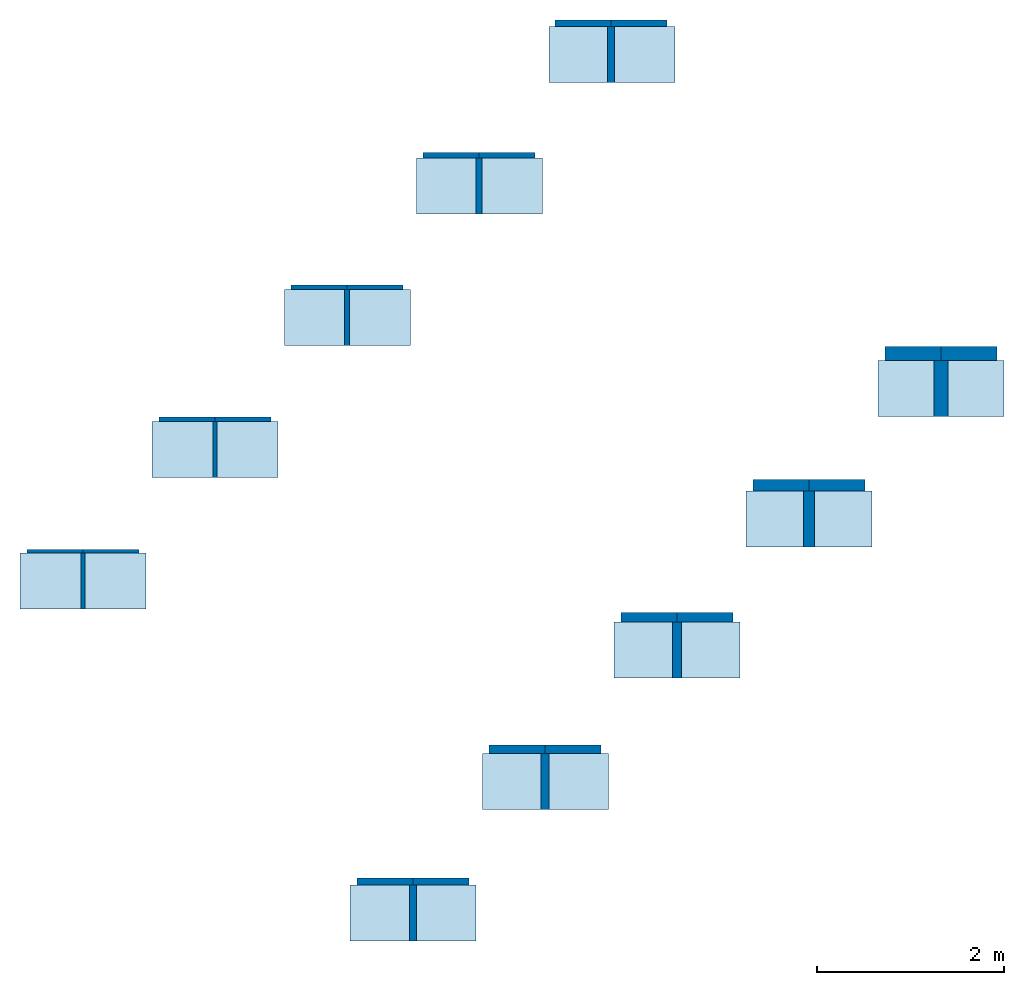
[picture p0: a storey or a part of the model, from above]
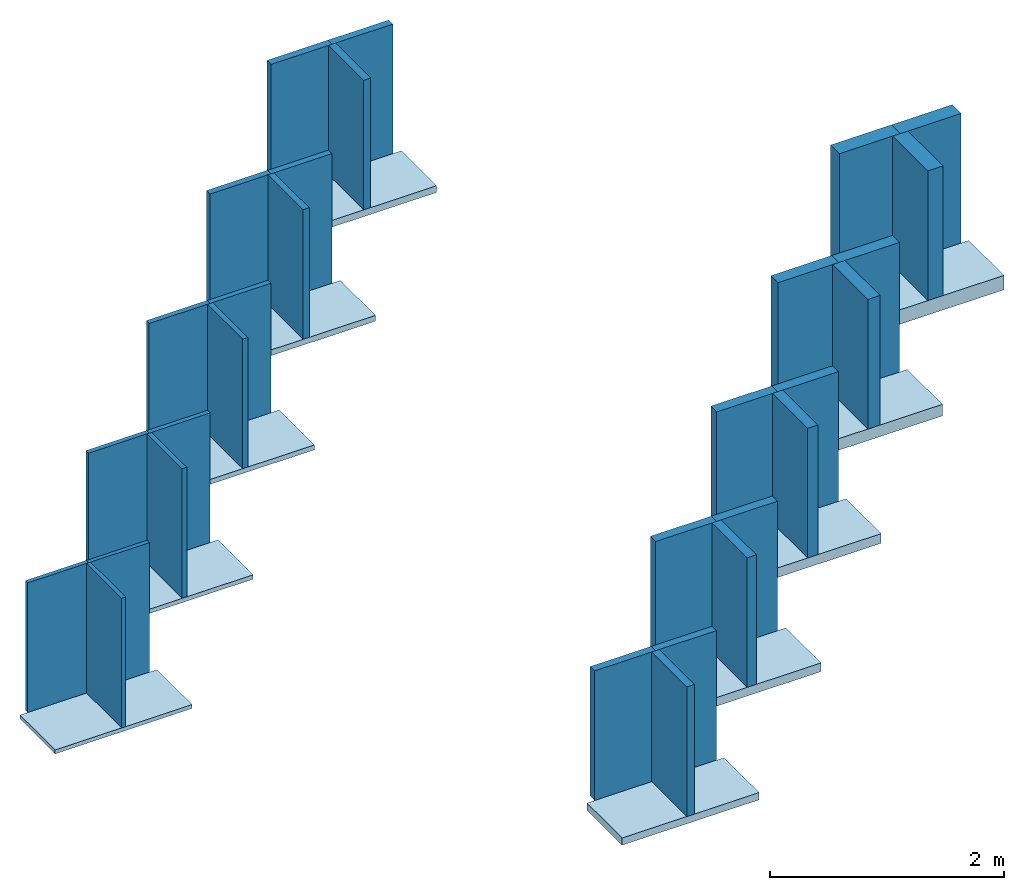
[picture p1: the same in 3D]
Properties of the parts of a building model (IFC2X3)

# File
Description: ViewDefinition [CoordinationView_V2.0, QuantityTakeOffAddOnView]
Time: 2023-01-18T09:23:17
Written by: The EXPRESS Data Manager Version 5.02.0100.07 : 28 Aug 2013
Made in: 21.1.70.21 - Exporter 21.1.70.21 - Alternate UI 21.1.70.21
Comment: STEP Physical File produced by: The EXPRESS Data Manager Version 5.02.0100.07 : 28 Aug 2013 * Module: EDMstepFileFactory/EDMstandAlone * Creation date: Wed Jan 18 09:23:17 2023 * Host: BIM-LT03 * Database: C:\Users\DONNEE~1\AppData\Local\Temp\6dfd9f73-01cb-4fe2-bb7c-203e315a706e\c4da6f99-adb1-409d-b0d4-b091b76bd9ac\ifc * Database version: 5507 * Database creation date: Wed Jan 18 09:23:16 2023 * Schema: IFC2X3 * Model: DataRepository.ifc * Model creation date: Wed Jan 18 09:23:16 2023 * Header model: DataRepository.ifc_HeaderModel * Header model creation date: Wed Jan 18 09:23:16 2023 * EDMuser: sdai-user * EDMgroup: sdai-group * License ID and type: 5605 : Permanent license. Expiry date: * EDMstepFileFactory options: 020000

# IfcSite, Default
RefLatitude: 42, 24, 53, 508911; RefLongitude: -71, -15, -29, -58837; RefElevation: 0 mm
Pset_ProductRequirements - Category: Project Information

# IfcBuilding
Pset_BuildingCommon - NumberOfStoreys: 1
Pset_ProductRequirements - Category: Project Information

# IfcBuildingStorey: Level:NL_00_niveau, Begane grond
LongName: Begane grond; Elevation: 0 mm
Pset_AirSideSystemInformation - Name: Begane grond
Pset_ProductRequirements - Name: Begane grond; Category: Levels

# IfcSlab: Floor:NLRS_23_FL_Acoustifit_100x600x1350mm, Floor:NLRS_23_FL_Acoustifit_100x600x1350mm:6533
In: Begane grond
Type - PredefinedType: FLOOR; Material: Knauf Insulation_Ecose® glaswol Acoustifit 100 mm
Type - Pset_ElementShading - Roughness: 304.8 mm
Type - Pset_ManufacturerTypeInformation - Manufacturer: Knauf Insulation B.V.
Type - Pset_ProductRequirements - Category: Floors
Type - Pset_QuantityTakeOff - Reference: Floor:NLRS_23_FL_Acoustifit_100x600x1350mm
Type - Pset_ReinforcementBarPitchOfSlab - Description: Acoustifit - 100mm; Reference: Floor:NLRS_23_FL_Acoustifit_100x600x1350mm
Type - Pset_SlabCommon - IsExternal: no; Reference: Floor:NLRS_23_FL_Acoustifit_100x600x1350mm; ThermalTransmittance: 0.37 kg/K/s3
Type - Pset_Floor_Acoustifit_LOD_200 - Assembly Code: 23; Type Image: Raster image: Acoustifit.jpg (2); Model: Acoustifit is een onbeklede glaswolplaat met ECOSE® Technology.; Manufacturer: Knauf Insulation B.V.; URL: www.knaufinsulation.nl; Description: Acoustifit - 100mm
Classification: 23 Vloeren (NL-SfB)
Pset_SlabCommon - LoadBearing: no; PitchAngle: 0 deg
Pset_Floor_Acoustifit_LOD_200 - Type: Floor: NLRS_23_FL_Acoustifit_100x600x1350mm
BaseQuantities - GrossArea: 0.81 m2; NetArea: 2.01 m2; GrossVolume: 81 m3; NetVolume: 0.081 m3; Perimeter: 3900 mm; Width: 100 mm

# IfcSlab: Floor:NLRS_23_FL_Acoustifit_120x600x1350mm, Floor:NLRS_23_FL_Acoustifit_120x600x1350mm:6542
In: Begane grond
Type - PredefinedType: FLOOR; Material: Knauf Insulation_Ecose® glaswol Acoustifit 120 mm
Type - Pset_ElementShading - Roughness: 304.8 mm
Type - Pset_ManufacturerTypeInformation - Manufacturer: Knauf Insulation B.V.
Type - Pset_ProductRequirements - Category: Floors
Type - Pset_QuantityTakeOff - Reference: Floor:NLRS_23_FL_Acoustifit_120x600x1350mm
Type - Pset_ReinforcementBarPitchOfSlab - Description: Acoustifit - 120mm; Reference: Floor:NLRS_23_FL_Acoustifit_120x600x1350mm
Type - Pset_SlabCommon - IsExternal: no; Reference: Floor:NLRS_23_FL_Acoustifit_120x600x1350mm; ThermalTransmittance: 0.308333 kg/K/s3
Type - Pset_Floor_Acoustifit_LOD_200 - Assembly Code: 23; Type Image: Raster image: Acoustifit.jpg (2); Model: Acoustifit is een onbeklede glaswolplaat met ECOSE® Technology.; Manufacturer: Knauf Insulation B.V.; URL: www.knaufinsulation.nl; Description: Acoustifit - 120mm
Classification: 23 Vloeren (NL-SfB)
Pset_SlabCommon - LoadBearing: no; PitchAngle: 0 deg
Pset_Floor_Acoustifit_LOD_200 - Type: Floor: NLRS_23_FL_Acoustifit_120x600x1350mm
BaseQuantities - GrossArea: 0.81 m2; NetArea: 2.088 m2; GrossVolume: 97.2 m3; NetVolume: 0.0972 m3; Perimeter: 3900 mm; Width: 120 mm

# IfcSlab: Floor:NLRS_23_FL_Acoustifit_150x600x1350mm, Floor:NLRS_23_FL_Acoustifit_150x600x1350mm:6551
In: Begane grond
Type - PredefinedType: FLOOR; Material: Knauf Insulation_Ecose® glaswol Acoustifit 150 mm
Type - Pset_ElementShading - Roughness: 304.8 mm
Type - Pset_ManufacturerTypeInformation - Manufacturer: Knauf Insulation B.V.
Type - Pset_ProductRequirements - Category: Floors
Type - Pset_QuantityTakeOff - Reference: Floor:NLRS_23_FL_Acoustifit_150x600x1350mm
Type - Pset_ReinforcementBarPitchOfSlab - Description: Acoustifit - 150mm; Reference: Floor:NLRS_23_FL_Acoustifit_150x600x1350mm
Type - Pset_SlabCommon - IsExternal: no; Reference: Floor:NLRS_23_FL_Acoustifit_150x600x1350mm; ThermalTransmittance: 0.246667 kg/K/s3
Type - Pset_Floor_Acoustifit_LOD_200 - Assembly Code: 23; Type Image: Raster image: Acoustifit.jpg (2); Model: Acoustifit is een onbeklede glaswolplaat met ECOSE® Technology.; Manufacturer: Knauf Insulation B.V.; URL: www.knaufinsulation.nl; Description: Acoustifit - 150mm
Classification: 23 Vloeren (NL-SfB)
Pset_SlabCommon - LoadBearing: no; PitchAngle: 0 deg
Pset_Floor_Acoustifit_LOD_200 - Type: Floor: NLRS_23_FL_Acoustifit_150x600x1350mm
BaseQuantities - GrossArea: 0.81 m2; NetArea: 2.205 m2; GrossVolume: 121.5 m3; NetVolume: 0.1215 m3; Perimeter: 3900 mm; Width: 150 mm

# IfcSlab: Floor:NLRS_23_FL_Acoustifit_40x600x1350mm, Floor:NLRS_23_FL_Acoustifit_40x600x1350mm:3702
In: Begane grond
Type - PredefinedType: FLOOR; Material: Knauf Insulation_Ecose® glaswol Acoustifit 40 mm
Type - Pset_ElementShading - Roughness: 304.8 mm
Type - Pset_ManufacturerTypeInformation - Manufacturer: Knauf Insulation B.V.
Type - Pset_ProductRequirements - Category: Floors
Type - Pset_QuantityTakeOff - Reference: Floor:NLRS_23_FL_Acoustifit_40x600x1350mm
Type - Pset_ReinforcementBarPitchOfSlab - Description: Acoustifit - 40mm; Reference: Floor:NLRS_23_FL_Acoustifit_40x600x1350mm
Type - Pset_SlabCommon - IsExternal: no; Reference: Floor:NLRS_23_FL_Acoustifit_40x600x1350mm; ThermalTransmittance: 0.925 kg/K/s3
Type - Pset_Floor_Acoustifit_LOD_200 - Assembly Code: 23; Type Image: Raster image: Acoustifit.jpg (2); Model: Acoustifit is een onbeklede glaswolplaat met ECOSE® Technology.; Manufacturer: Knauf Insulation B.V.; URL: www.knaufinsulation.nl; Description: Acoustifit - 40mm
Classification: 23 Vloeren (NL-SfB)
Pset_SlabCommon - LoadBearing: no; PitchAngle: 0 deg
Pset_Floor_Acoustifit_LOD_200 - Type: Floor: NLRS_23_FL_Acoustifit_40x600x1350mm
BaseQuantities - GrossArea: 0.81 m2; NetArea: 1.776 m2; GrossVolume: 32.4 m3; NetVolume: 0.0324 m3; Perimeter: 3900 mm; Width: 40 mm

# IfcSlab: Floor:NLRS_23_FL_Acoustifit_45x600x1350mm, Floor:NLRS_23_FL_Acoustifit_45x600x1350mm:5869
In: Begane grond
Type - PredefinedType: FLOOR; Material: Knauf Insulation_Ecose® glaswol Acoustifit 45 mm
Type - Pset_ElementShading - Roughness: 304.8 mm
Type - Pset_ManufacturerTypeInformation - Manufacturer: Knauf Insulation B.V.
Type - Pset_ProductRequirements - Category: Floors
Type - Pset_QuantityTakeOff - Reference: Floor:NLRS_23_FL_Acoustifit_45x600x1350mm
Type - Pset_ReinforcementBarPitchOfSlab - Description: Acoustifit - 45mm; Reference: Floor:NLRS_23_FL_Acoustifit_45x600x1350mm
Type - Pset_SlabCommon - IsExternal: no; Reference: Floor:NLRS_23_FL_Acoustifit_45x600x1350mm; ThermalTransmittance: 0.822222 kg/K/s3
Type - Pset_Floor_Acoustifit_LOD_200 - Assembly Code: 23; Type Image: Raster image: Acoustifit.jpg (2); Model: Acoustifit is een onbeklede glaswolplaat met ECOSE® Technology.; Manufacturer: Knauf Insulation B.V.; URL: www.knaufinsulation.nl; Description: Acoustifit - 45mm
Classification: 23 Vloeren (NL-SfB)
Pset_SlabCommon - LoadBearing: no; PitchAngle: 0 deg
Pset_Floor_Acoustifit_LOD_200 - Type: Floor: NLRS_23_FL_Acoustifit_45x600x1350mm
BaseQuantities - GrossArea: 0.81 m2; NetArea: 1.7955 m2; GrossVolume: 36.45 m3; NetVolume: 0.03645 m3; Perimeter: 3900 mm; Width: 45 mm

# IfcSlab: Floor:NLRS_23_FL_Acoustifit_50x600x1350mm, Floor:NLRS_23_FL_Acoustifit_50x600x1350mm:5943
In: Begane grond
Type - PredefinedType: FLOOR; Material: Knauf Insulation_Ecose® glaswol Acoustifit 50 mm
Type - Pset_ElementShading - Roughness: 304.8 mm
Type - Pset_ManufacturerTypeInformation - Manufacturer: Knauf Insulation B.V.
Type - Pset_ProductRequirements - Category: Floors
Type - Pset_QuantityTakeOff - Reference: Floor:NLRS_23_FL_Acoustifit_50x600x1350mm
Type - Pset_ReinforcementBarPitchOfSlab - Description: Acoustifit - 50mm; Reference: Floor:NLRS_23_FL_Acoustifit_50x600x1350mm
Type - Pset_SlabCommon - IsExternal: no; Reference: Floor:NLRS_23_FL_Acoustifit_50x600x1350mm; ThermalTransmittance: 0.74 kg/K/s3
Type - Pset_Floor_Acoustifit_LOD_200 - Assembly Code: 23; Type Image: Raster image: Acoustifit.jpg (2); Model: Acoustifit is een onbeklede glaswolplaat met ECOSE® Technology.; Manufacturer: Knauf Insulation B.V.; URL: www.knaufinsulation.nl; Description: Acoustifit - 50mm
Classification: 23 Vloeren (NL-SfB)
Pset_SlabCommon - LoadBearing: no; PitchAngle: 0 deg
Pset_Floor_Acoustifit_LOD_200 - Type: Floor: NLRS_23_FL_Acoustifit_50x600x1350mm
BaseQuantities - GrossArea: 0.81 m2; NetArea: 1.815 m2; GrossVolume: 40.5 m3; NetVolume: 0.0405 m3; Perimeter: 3900 mm; Width: 50 mm

# IfcSlab: Floor:NLRS_23_FL_Acoustifit_60x600x1350mm, Floor:NLRS_23_FL_Acoustifit_60x600x1350mm:5952
In: Begane grond
Type - PredefinedType: FLOOR; Material: Knauf Insulation_Ecose® glaswol Acoustifit 60 mm
Type - Pset_ElementShading - Roughness: 304.8 mm
Type - Pset_ManufacturerTypeInformation - Manufacturer: Knauf Insulation B.V.
Type - Pset_ProductRequirements - Category: Floors
Type - Pset_QuantityTakeOff - Reference: Floor:NLRS_23_FL_Acoustifit_60x600x1350mm
Type - Pset_ReinforcementBarPitchOfSlab - Description: Acoustifit - 60mm; Reference: Floor:NLRS_23_FL_Acoustifit_60x600x1350mm
Type - Pset_SlabCommon - IsExternal: no; Reference: Floor:NLRS_23_FL_Acoustifit_60x600x1350mm; ThermalTransmittance: 0.616667 kg/K/s3
Type - Pset_Floor_Acoustifit_LOD_200 - Assembly Code: 23; Type Image: Raster image: Acoustifit.jpg (2); Model: Acoustifit is een onbeklede glaswolplaat met ECOSE® Technology.; Manufacturer: Knauf Insulation B.V.; URL: www.knaufinsulation.nl; Description: Acoustifit - 60mm
Classification: 23 Vloeren (NL-SfB)
Pset_SlabCommon - LoadBearing: no; PitchAngle: 0 deg
Pset_Floor_Acoustifit_LOD_200 - Type: Floor: NLRS_23_FL_Acoustifit_60x600x1350mm
BaseQuantities - GrossArea: 0.81 m2; NetArea: 1.854 m2; GrossVolume: 48.6 m3; NetVolume: 0.0486 m3; Perimeter: 3900 mm; Width: 60 mm

# IfcSlab: Floor:NLRS_23_FL_Acoustifit_70x600x1350mm, Floor:NLRS_23_FL_Acoustifit_70x600x1350mm:5961
In: Begane grond
Type - PredefinedType: FLOOR; Material: Knauf Insulation_Ecose® glaswol Acoustifit 70 mm
Type - Pset_ElementShading - Roughness: 304.8 mm
Type - Pset_ManufacturerTypeInformation - Manufacturer: Knauf Insulation B.V.
Type - Pset_ProductRequirements - Category: Floors
Type - Pset_QuantityTakeOff - Reference: Floor:NLRS_23_FL_Acoustifit_70x600x1350mm
Type - Pset_ReinforcementBarPitchOfSlab - Description: Acoustifit - 70mm; Reference: Floor:NLRS_23_FL_Acoustifit_70x600x1350mm
Type - Pset_SlabCommon - IsExternal: no; Reference: Floor:NLRS_23_FL_Acoustifit_70x600x1350mm; ThermalTransmittance: 0.528571 kg/K/s3
Type - Pset_Floor_Acoustifit_LOD_200 - Assembly Code: 23; Type Image: Raster image: Acoustifit.jpg (2); Model: Acoustifit is een onbeklede glaswolplaat met ECOSE® Technology.; Manufacturer: Knauf Insulation B.V.; URL: www.knaufinsulation.nl; Description: Acoustifit - 70mm
Classification: 23 Vloeren (NL-SfB)
Pset_SlabCommon - LoadBearing: no; PitchAngle: 0 deg
Pset_Floor_Acoustifit_LOD_200 - Type: Floor: NLRS_23_FL_Acoustifit_70x600x1350mm
BaseQuantities - GrossArea: 0.81 m2; NetArea: 1.893 m2; GrossVolume: 56.7 m3; NetVolume: 0.0567 m3; Perimeter: 3900 mm; Width: 70 mm

# IfcSlab: Floor:NLRS_23_FL_Acoustifit_75x600x1350mm, Floor:NLRS_23_FL_Acoustifit_75x600x1350mm:6406
In: Begane grond
Type - PredefinedType: FLOOR; Material: Knauf Insulation_Ecose® glaswol Acoustifit 75 mm
Type - Pset_ElementShading - Roughness: 304.8 mm
Type - Pset_ManufacturerTypeInformation - Manufacturer: Knauf Insulation B.V.
Type - Pset_ProductRequirements - Category: Floors
Type - Pset_QuantityTakeOff - Reference: Floor:NLRS_23_FL_Acoustifit_75x600x1350mm
Type - Pset_ReinforcementBarPitchOfSlab - Description: Acoustifit - 75mm; Reference: Floor:NLRS_23_FL_Acoustifit_75x600x1350mm
Type - Pset_SlabCommon - IsExternal: no; Reference: Floor:NLRS_23_FL_Acoustifit_75x600x1350mm; ThermalTransmittance: 0.493333 kg/K/s3
Type - Pset_Floor_Acoustifit_LOD_200 - Assembly Code: 23; Type Image: Raster image: Acoustifit.jpg (2); Model: Acoustifit is een onbeklede glaswolplaat met ECOSE® Technology.; Manufacturer: Knauf Insulation B.V.; URL: www.knaufinsulation.nl; Description: Acoustifit - 75mm
Classification: 23 Vloeren (NL-SfB)
Pset_SlabCommon - LoadBearing: no; PitchAngle: 0 deg
Pset_Floor_Acoustifit_LOD_200 - Type: Floor: NLRS_23_FL_Acoustifit_75x600x1350mm
BaseQuantities - GrossArea: 0.81 m2; NetArea: 1.9125 m2; GrossVolume: 60.75 m3; NetVolume: 0.06075 m3; Perimeter: 3900 mm; Width: 75 mm

# IfcSlab: Floor:NLRS_23_FL_Acoustifit_90x600x1350mm, Floor:NLRS_23_FL_Acoustifit_90x600x1350mm:6471
In: Begane grond
Type - PredefinedType: FLOOR; Material: Knauf Insulation_Ecose® glaswol Acoustifit 90 mm
Type - Pset_ElementShading - Roughness: 304.8 mm
Type - Pset_ManufacturerTypeInformation - Manufacturer: Knauf Insulation B.V.
Type - Pset_ProductRequirements - Category: Floors
Type - Pset_QuantityTakeOff - Reference: Floor:NLRS_23_FL_Acoustifit_90x600x1350mm
Type - Pset_ReinforcementBarPitchOfSlab - Description: Acoustifit - 90mm; Reference: Floor:NLRS_23_FL_Acoustifit_90x600x1350mm
Type - Pset_SlabCommon - IsExternal: no; Reference: Floor:NLRS_23_FL_Acoustifit_90x600x1350mm; ThermalTransmittance: 0.411111 kg/K/s3
Type - Pset_Floor_Acoustifit_LOD_200 - Assembly Code: 23; Type Image: Raster image: Acoustifit.jpg (2); Model: Acoustifit is een onbeklede glaswolplaat met ECOSE® Technology.; Manufacturer: Knauf Insulation B.V.; URL: www.knaufinsulation.nl; Description: Acoustifit - 90mm
Classification: 23 Vloeren (NL-SfB)
Pset_SlabCommon - LoadBearing: no; PitchAngle: 0 deg
Pset_Floor_Acoustifit_LOD_200 - Type: Floor: NLRS_23_FL_Acoustifit_90x600x1350mm
BaseQuantities - GrossArea: 0.81 m2; NetArea: 1.971 m2; GrossVolume: 72.9 m3; NetVolume: 0.0729 m3; Perimeter: 3900 mm; Width: 90 mm

# IfcWallStandardCase: Basic Wall:NLRS_21_WA__Acoustifit_100x600x1350mm (3)
In: Begane grond
Type - PredefinedType: STANDARD; Material: Knauf Insulation_Ecose® glaswol Acoustifit 100 mm
Type - Pset_ElementShading - Roughness: 304.8 mm
Type - Pset_ManufacturerTypeInformation - Manufacturer: Knauf Insulation B.V.
Type - Pset_ProductRequirements - Category: Walls
Type - Pset_QuantityTakeOff - Reference: Basic Wall:NLRS_21_WA__Acoustifit_100x600x1350mm
Type - Pset_ReinforcementBarPitchOfWall - Description: Acoustifit - 100mm Acoustifit - 100mm; Reference: Basic Wall:NLRS_21_WA__Acoustifit_100x600x1350mm
Type - Pset_WallCommon - IsExternal: no; Reference: Basic Wall:NLRS_21_WA__Acoustifit_100x600x1350mm; ThermalTransmittance: 0.37 kg/K/s3
Type - Pset_Wall_Acoustifit_LOD_200 - Assembly Code: 21; Type Image: Raster image: Acoustifit.jpg (2); Model: Acoustifit is een onbeklede glaswolplaat met ECOSE® Technology.; Manufacturer: Knauf Insulation B.V.; URL: www.knaufinsulation.nl; Description: Acoustifit - 100mm Acoustifit - 100mm
Classification: 21 Buitenwanden (NL-SfB)
BaseQuantities - Height: 1350 mm; Length: 600 mm; Width: 100 mm; GrossFootprintArea: 0.06 m2; NetVolume: 81000000 m3; NetSideArea: 810000 m2
Pset_WallCommon - IsExternal: yes; ExtendToStructure: no; LoadBearing: no
Pset_Wall_Acoustifit_LOD_200 - Type: Basic Wall: NLRS_21_WA__Acoustifit_100x600x1350mm
Name (Basic Wall:NLRS_21_WA__Acoustifit_100x600x1350mm:...)
4728
4729
4730

# IfcWallStandardCase: Basic Wall:NLRS_21_WA__Acoustifit_120x600x1350mm (3)
In: Begane grond
Type - PredefinedType: STANDARD; Material: Knauf Insulation_Ecose® glaswol Acoustifit 120 mm
Type - Pset_ElementShading - Roughness: 304.8 mm
Type - Pset_ManufacturerTypeInformation - Manufacturer: Knauf Insulation B.V.
Type - Pset_ProductRequirements - Category: Walls
Type - Pset_QuantityTakeOff - Reference: Basic Wall:NLRS_21_WA__Acoustifit_120x600x1350mm
Type - Pset_ReinforcementBarPitchOfWall - Description: Acoustifit - 120mm; Reference: Basic Wall:NLRS_21_WA__Acoustifit_120x600x1350mm
Type - Pset_WallCommon - IsExternal: no; Reference: Basic Wall:NLRS_21_WA__Acoustifit_120x600x1350mm; ThermalTransmittance: 0.308333 kg/K/s3
Type - Pset_Wall_Acoustifit_LOD_200 - Assembly Code: 21; Type Image: Raster image: Acoustifit.jpg (2); Model: Acoustifit is een onbeklede glaswolplaat met ECOSE® Technology.; Manufacturer: Knauf Insulation B.V.; URL: www.knaufinsulation.nl; Description: Acoustifit - 120mm
Classification: 21 Buitenwanden (NL-SfB)
BaseQuantities - Height: 1350 mm; Length: 600 mm; Width: 120 mm; GrossFootprintArea: 0.072 m2; NetVolume: 97200000 m3; NetSideArea: 810000 m2
Pset_WallCommon - IsExternal: yes; ExtendToStructure: no; LoadBearing: no
Pset_Wall_Acoustifit_LOD_200 - Type: Basic Wall: NLRS_21_WA__Acoustifit_120x600x1350mm
Name (Basic Wall:NLRS_21_WA__Acoustifit_120x600x1350mm:...)
4731
4732
4733

# IfcWallStandardCase: Basic Wall:NLRS_21_WA__Acoustifit_150x600x1350mm (3)
In: Begane grond
Type - PredefinedType: STANDARD; Material: Knauf Insulation_Ecose® glaswol Acoustifit 150 mm
Type - Pset_ElementShading - Roughness: 304.8 mm
Type - Pset_ManufacturerTypeInformation - Manufacturer: Knauf Insulation B.V.
Type - Pset_ProductRequirements - Category: Walls
Type - Pset_QuantityTakeOff - Reference: Basic Wall:NLRS_21_WA__Acoustifit_150x600x1350mm
Type - Pset_ReinforcementBarPitchOfWall - Description: Acoustifit - 150mm; Reference: Basic Wall:NLRS_21_WA__Acoustifit_150x600x1350mm
Type - Pset_WallCommon - IsExternal: no; Reference: Basic Wall:NLRS_21_WA__Acoustifit_150x600x1350mm; ThermalTransmittance: 0.246667 kg/K/s3
Type - Pset_Wall_Acoustifit_LOD_200 - Assembly Code: 21; Type Image: Raster image: Acoustifit.jpg (2); Model: Acoustifit is een onbeklede glaswolplaat met ECOSE® Technology.; Manufacturer: Knauf Insulation B.V.; URL: www.knaufinsulation.nl; Description: Acoustifit - 150mm
Classification: 21 Buitenwanden (NL-SfB)
BaseQuantities - Height: 1350 mm; Length: 600 mm; Width: 150 mm; GrossFootprintArea: 0.09 m2; NetVolume: 121500000 m3; NetSideArea: 810000 m2
Pset_WallCommon - IsExternal: yes; ExtendToStructure: no; LoadBearing: no
Pset_Wall_Acoustifit_LOD_200 - Type: Basic Wall: NLRS_21_WA__Acoustifit_150x600x1350mm
Name (Basic Wall:NLRS_21_WA__Acoustifit_150x600x1350mm:...)
4734
4735
4736

# IfcWallStandardCase: Basic Wall:NLRS_21_WA__Acoustifit_40x600x1350mm (3)
In: Begane grond
Type - PredefinedType: STANDARD; Material: Knauf Insulation_Ecose® glaswol Acoustifit 40 mm
Type - Pset_ElementShading - Roughness: 304.8 mm
Type - Pset_ManufacturerTypeInformation - Manufacturer: Knauf Insulation B.V.
Type - Pset_ProductRequirements - Category: Walls
Type - Pset_QuantityTakeOff - Reference: Basic Wall:NLRS_21_WA__Acoustifit_40x600x1350mm
Type - Pset_ReinforcementBarPitchOfWall - Description: Acoustifit - 40mm; Reference: Basic Wall:NLRS_21_WA__Acoustifit_40x600x1350mm
Type - Pset_WallCommon - Reference: Basic Wall:NLRS_21_WA__Acoustifit_40x600x1350mm; ThermalTransmittance: 0.925 kg/K/s3; IsExternal: no
Type - Pset_Wall_Acoustifit_LOD_200 - Assembly Code: 21; Type Image: Raster image: Acoustifit.jpg (2); Model: Acoustifit is een onbeklede glaswolplaat met ECOSE® Technology.; Manufacturer: Knauf Insulation B.V.; URL: www.knaufinsulation.nl; Description: Acoustifit - 40mm
Classification: 21 Buitenwanden (NL-SfB)
BaseQuantities - Height: 1350 mm; Length: 600 mm; Width: 40 mm; GrossFootprintArea: 0.024 m2; NetVolume: 32400000 m3; NetSideArea: 810000 m2
Pset_WallCommon - IsExternal: yes; ExtendToStructure: no; LoadBearing: no
Pset_Wall_Acoustifit_LOD_200 - Type: Basic Wall: NLRS_21_WA__Acoustifit_40x600x1350mm
Name (Basic Wall:NLRS_21_WA__Acoustifit_40x600x1350mm:...)
2453
2588
4073

# IfcWallStandardCase: Basic Wall:NLRS_21_WA__Acoustifit_45x600x1350mm (3)
In: Begane grond
Type - PredefinedType: STANDARD; Material: Knauf Insulation_Ecose® glaswol Acoustifit 45 mm
Type - Pset_ElementShading - Roughness: 304.8 mm
Type - Pset_ManufacturerTypeInformation - Manufacturer: Knauf Insulation B.V.
Type - Pset_ProductRequirements - Category: Walls
Type - Pset_QuantityTakeOff - Reference: Basic Wall:NLRS_21_WA__Acoustifit_45x600x1350mm
Type - Pset_ReinforcementBarPitchOfWall - Description: Acoustifit - 45mm - 45mm; Reference: Basic Wall:NLRS_21_WA__Acoustifit_45x600x1350mm
Type - Pset_WallCommon - IsExternal: no; Reference: Basic Wall:NLRS_21_WA__Acoustifit_45x600x1350mm; ThermalTransmittance: 0.822222 kg/K/s3
Type - Pset_Wall_Acoustifit_LOD_200 - Assembly Code: 21; Type Image: Raster image: Acoustifit.jpg (2); Model: Acoustifit is een onbeklede glaswolplaat met ECOSE® Technology.; Manufacturer: Knauf Insulation B.V.; URL: www.knaufinsulation.nl; Description: Acoustifit - 45mm - 45mm
Classification: 21 Buitenwanden (NL-SfB)
BaseQuantities - Height: 1350 mm; Length: 600 mm; Width: 45 mm; GrossFootprintArea: 0.027 m2; NetVolume: 36450000 m3; NetSideArea: 810000 m2
Pset_WallCommon - IsExternal: yes; ExtendToStructure: no; LoadBearing: no
Pset_Wall_Acoustifit_LOD_200 - Type: Basic Wall: NLRS_21_WA__Acoustifit_45x600x1350mm
Name (Basic Wall:NLRS_21_WA__Acoustifit_45x600x1350mm:...)
4397
4398
4400

# IfcWallStandardCase: Basic Wall:NLRS_21_WA__Acoustifit_50x600x1350mm (3)
In: Begane grond
Type - PredefinedType: STANDARD; Material: Knauf Insulation_Ecose® glaswol Acoustifit 50 mm
Type - Pset_ElementShading - Roughness: 304.8 mm
Type - Pset_ManufacturerTypeInformation - Manufacturer: Knauf Insulation B.V.
Type - Pset_ProductRequirements - Category: Walls
Type - Pset_QuantityTakeOff - Reference: Basic Wall:NLRS_21_WA__Acoustifit_50x600x1350mm
Type - Pset_ReinforcementBarPitchOfWall - Description: Acoustifit - 50mm; Reference: Basic Wall:NLRS_21_WA__Acoustifit_50x600x1350mm
Type - Pset_WallCommon - IsExternal: no; Reference: Basic Wall:NLRS_21_WA__Acoustifit_50x600x1350mm; ThermalTransmittance: 0.74 kg/K/s3
Type - Pset_Wall_Acoustifit_LOD_200 - Assembly Code: 21; Type Image: Raster image: Acoustifit.jpg (2); Model: Acoustifit is een onbeklede glaswolplaat met ECOSE® Technology.; Manufacturer: Knauf Insulation B.V.; URL: www.knaufinsulation.nl; Description: Acoustifit - 50mm
Classification: 21 Buitenwanden (NL-SfB)
BaseQuantities - Height: 1350 mm; Length: 600 mm; Width: 50 mm; GrossFootprintArea: 0.03 m2; NetVolume: 40500000 m3; NetSideArea: 810000 m2
Pset_WallCommon - IsExternal: yes; ExtendToStructure: no; LoadBearing: no
Pset_Wall_Acoustifit_LOD_200 - Type: Basic Wall: NLRS_21_WA__Acoustifit_50x600x1350mm
Name (Basic Wall:NLRS_21_WA__Acoustifit_50x600x1350mm:...)
4441
4442
4443

# IfcWallStandardCase: Basic Wall:NLRS_21_WA__Acoustifit_60x600x1350mm (3)
In: Begane grond
Type - PredefinedType: STANDARD; Material: Knauf Insulation_Ecose® glaswol Acoustifit 60 mm
Type - Pset_ElementShading - Roughness: 304.8 mm
Type - Pset_ManufacturerTypeInformation - Manufacturer: Knauf Insulation B.V.
Type - Pset_ProductRequirements - Category: Walls
Type - Pset_QuantityTakeOff - Reference: Basic Wall:NLRS_21_WA__Acoustifit_60x600x1350mm
Type - Pset_ReinforcementBarPitchOfWall - Description: Acoustifit - 60mm; Reference: Basic Wall:NLRS_21_WA__Acoustifit_60x600x1350mm
Type - Pset_WallCommon - IsExternal: no; Reference: Basic Wall:NLRS_21_WA__Acoustifit_60x600x1350mm; ThermalTransmittance: 0.616667 kg/K/s3
Type - Pset_Wall_Acoustifit_LOD_200 - Assembly Code: 21; Type Image: Raster image: Acoustifit.jpg (2); Model: Acoustifit is een onbeklede glaswolplaat met ECOSE® Technology.; Manufacturer: Knauf Insulation B.V.; URL: www.knaufinsulation.nl; Description: Acoustifit - 60mm
Classification: 21 Buitenwanden (NL-SfB)
BaseQuantities - Height: 1350 mm; Length: 600 mm; Width: 60 mm; GrossFootprintArea: 0.036 m2; NetVolume: 48600000 m3; NetSideArea: 810000 m2
Pset_WallCommon - IsExternal: yes; ExtendToStructure: no; LoadBearing: no
Pset_Wall_Acoustifit_LOD_200 - Type: Basic Wall: NLRS_21_WA__Acoustifit_60x600x1350mm
Name (Basic Wall:NLRS_21_WA__Acoustifit_60x600x1350mm:...)
4592
4593
4594

# IfcWallStandardCase: Basic Wall:NLRS_21_WA__Acoustifit_70x600x1350mm (3)
In: Begane grond
Type - PredefinedType: STANDARD; Material: Knauf Insulation_Ecose® glaswol Acoustifit 70 mm
Type - Pset_ElementShading - Roughness: 304.8 mm
Type - Pset_ManufacturerTypeInformation - Manufacturer: Knauf Insulation B.V.
Type - Pset_ProductRequirements - Category: Walls
Type - Pset_QuantityTakeOff - Reference: Basic Wall:NLRS_21_WA__Acoustifit_70x600x1350mm
Type - Pset_ReinforcementBarPitchOfWall - Description: Acoustifit - 70mm; Reference: Basic Wall:NLRS_21_WA__Acoustifit_70x600x1350mm
Type - Pset_WallCommon - IsExternal: no; Reference: Basic Wall:NLRS_21_WA__Acoustifit_70x600x1350mm; ThermalTransmittance: 0.528571 kg/K/s3
Type - Pset_Wall_Acoustifit_LOD_200 - Assembly Code: 21; Type Image: Raster image: Acoustifit.jpg (2); Model: Acoustifit is een onbeklede glaswolplaat met ECOSE® Technology.; Manufacturer: Knauf Insulation B.V.; URL: www.knaufinsulation.nl; Description: Acoustifit - 70mm
Classification: 21 Buitenwanden (NL-SfB)
BaseQuantities - Height: 1350 mm; Length: 600 mm; Width: 70 mm; GrossFootprintArea: 0.042 m2; NetVolume: 56700000 m3; NetSideArea: 810000 m2
Pset_WallCommon - IsExternal: yes; ExtendToStructure: no; LoadBearing: no
Pset_Wall_Acoustifit_LOD_200 - Type: Basic Wall: NLRS_21_WA__Acoustifit_70x600x1350mm
Name (Basic Wall:NLRS_21_WA__Acoustifit_70x600x1350mm:...)
4655
4656
4657

# IfcWallStandardCase: Basic Wall:NLRS_21_WA__Acoustifit_75x600x1350mm (3)
In: Begane grond
Type - PredefinedType: STANDARD; Material: Knauf Insulation_Ecose® glaswol Acoustifit 75 mm
Type - Pset_ElementShading - Roughness: 304.8 mm
Type - Pset_ManufacturerTypeInformation - Manufacturer: Knauf Insulation B.V.
Type - Pset_ProductRequirements - Category: Walls
Type - Pset_QuantityTakeOff - Reference: Basic Wall:NLRS_21_WA__Acoustifit_75x600x1350mm
Type - Pset_ReinforcementBarPitchOfWall - Description: Acoustifit - 75mm; Reference: Basic Wall:NLRS_21_WA__Acoustifit_75x600x1350mm
Type - Pset_WallCommon - IsExternal: no; Reference: Basic Wall:NLRS_21_WA__Acoustifit_75x600x1350mm; ThermalTransmittance: 0.493333 kg/K/s3
Type - Pset_Wall_Acoustifit_LOD_200 - Assembly Code: 21; Type Image: Raster image: Acoustifit.jpg (2); Model: Acoustifit is een onbeklede glaswolplaat met ECOSE® Technology.; Manufacturer: Knauf Insulation B.V.; URL: www.knaufinsulation.nl; Description: Acoustifit - 75mm
Classification: 21 Buitenwanden (NL-SfB)
BaseQuantities - Height: 1350 mm; Length: 600 mm; Width: 75 mm; GrossFootprintArea: 0.045 m2; NetVolume: 60750000 m3; NetSideArea: 810000 m2
Pset_WallCommon - IsExternal: yes; ExtendToStructure: no; LoadBearing: no
Pset_Wall_Acoustifit_LOD_200 - Type: Basic Wall: NLRS_21_WA__Acoustifit_75x600x1350mm
Name (Basic Wall:NLRS_21_WA__Acoustifit_75x600x1350mm:...)
4721
4722
4724

# IfcWallStandardCase: Basic Wall:NLRS_21_WA__Acoustifit_90x600x1350mm (3)
In: Begane grond
Type - PredefinedType: STANDARD; Material: Knauf Insulation_Ecose® glaswol Acoustifit 90 mm
Type - Pset_ElementShading - Roughness: 304.8 mm
Type - Pset_ManufacturerTypeInformation - Manufacturer: Knauf Insulation B.V.
Type - Pset_ProductRequirements - Category: Walls
Type - Pset_QuantityTakeOff - Reference: Basic Wall:NLRS_21_WA__Acoustifit_90x600x1350mm
Type - Pset_ReinforcementBarPitchOfWall - Description: Acoustifit - 90mm; Reference: Basic Wall:NLRS_21_WA__Acoustifit_90x600x1350mm
Type - Pset_WallCommon - IsExternal: no; Reference: Basic Wall:NLRS_21_WA__Acoustifit_90x600x1350mm; ThermalTransmittance: 0.411111 kg/K/s3
Type - Pset_Wall_Acoustifit_LOD_200 - Assembly Code: 21; Type Image: Raster image: Acoustifit.jpg (2); Model: Acoustifit is een onbeklede glaswolplaat met ECOSE® Technology.; Manufacturer: Knauf Insulation B.V.; URL: www.knaufinsulation.nl; Description: Acoustifit - 90mm
Classification: 21 Buitenwanden (NL-SfB)
BaseQuantities - Height: 1350 mm; Length: 600 mm; Width: 90 mm; GrossFootprintArea: 0.054 m2; NetVolume: 72900000 m3; NetSideArea: 810000 m2
Pset_WallCommon - IsExternal: yes; ExtendToStructure: no; LoadBearing: no
Pset_Wall_Acoustifit_LOD_200 - Type: Basic Wall: NLRS_21_WA__Acoustifit_90x600x1350mm
Name (Basic Wall:NLRS_21_WA__Acoustifit_90x600x1350mm:...)
4725
4726
4727
